VERSION 5.7 ;
BUSBITCHARS "[]" ;
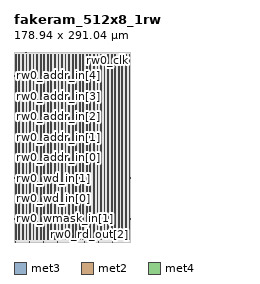
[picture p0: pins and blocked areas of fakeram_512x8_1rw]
MACRO fakeram_512x8_1rw
  FOREIGN fakeram_512x8_1rw 0 0 ;
  SYMMETRY X Y R90 ;
  SIZE 178.940 BY 291.040 ;
  CLASS BLOCK ;
  PIN rw0_wmask_in[0]
    DIRECTION INPUT ;
    USE SIGNAL ;
    SHAPE ABUTMENT ;
    PORT
      LAYER met3 ;
      RECT 0.000 3.930 0.900 4.230 ;
    END
  END rw0_wmask_in[0]
  PIN rw0_wmask_in[1]
    DIRECTION INPUT ;
    USE SIGNAL ;
    SHAPE ABUTMENT ;
    PORT
      LAYER met3 ;
      RECT 0.000 35.210 0.900 35.510 ;
    END
  END rw0_wmask_in[1]
  PIN rw0_wmask_in[2]
    DIRECTION INPUT ;
    USE SIGNAL ;
    SHAPE ABUTMENT ;
    PORT
      LAYER met3 ;
      RECT 178.040 3.930 178.940 4.230 ;
    END
  END rw0_wmask_in[2]
  PIN rw0_wmask_in[3]
    DIRECTION INPUT ;
    USE SIGNAL ;
    SHAPE ABUTMENT ;
    PORT
      LAYER met3 ;
      RECT 178.040 35.210 178.940 35.510 ;
    END
  END rw0_wmask_in[3]
  PIN rw0_wmask_in[4]
    DIRECTION INPUT ;
    USE SIGNAL ;
    SHAPE ABUTMENT ;
    PORT
      LAYER met2 ;
      RECT 2.690 290.620 2.830 291.040 ;
    END
  END rw0_wmask_in[4]
  PIN rw0_wmask_in[5]
    DIRECTION INPUT ;
    USE SIGNAL ;
    SHAPE ABUTMENT ;
    PORT
      LAYER met2 ;
      RECT 18.330 290.620 18.470 291.040 ;
    END
  END rw0_wmask_in[5]
  PIN rw0_wmask_in[6]
    DIRECTION INPUT ;
    USE SIGNAL ;
    SHAPE ABUTMENT ;
    PORT
      LAYER met2 ;
      RECT 33.970 290.620 34.110 291.040 ;
    END
  END rw0_wmask_in[6]
  PIN rw0_wmask_in[7]
    DIRECTION INPUT ;
    USE SIGNAL ;
    SHAPE ABUTMENT ;
    PORT
      LAYER met2 ;
      RECT 49.610 290.620 49.750 291.040 ;
    END
  END rw0_wmask_in[7]
  PIN rw0_wd_in[0]
    DIRECTION INPUT ;
    USE SIGNAL ;
    SHAPE ABUTMENT ;
    PORT
      LAYER met3 ;
      RECT 0.000 66.490 0.900 66.790 ;
    END
  END rw0_wd_in[0]
  PIN rw0_wd_in[1]
    DIRECTION INPUT ;
    USE SIGNAL ;
    SHAPE ABUTMENT ;
    PORT
      LAYER met3 ;
      RECT 0.000 97.770 0.900 98.070 ;
    END
  END rw0_wd_in[1]
  PIN rw0_wd_in[2]
    DIRECTION INPUT ;
    USE SIGNAL ;
    SHAPE ABUTMENT ;
    PORT
      LAYER met3 ;
      RECT 178.040 66.490 178.940 66.790 ;
    END
  END rw0_wd_in[2]
  PIN rw0_wd_in[3]
    DIRECTION INPUT ;
    USE SIGNAL ;
    SHAPE ABUTMENT ;
    PORT
      LAYER met3 ;
      RECT 178.040 97.770 178.940 98.070 ;
    END
  END rw0_wd_in[3]
  PIN rw0_wd_in[4]
    DIRECTION INPUT ;
    USE SIGNAL ;
    SHAPE ABUTMENT ;
    PORT
      LAYER met2 ;
      RECT 2.690 0.000 2.830 0.420 ;
    END
  END rw0_wd_in[4]
  PIN rw0_wd_in[5]
    DIRECTION INPUT ;
    USE SIGNAL ;
    SHAPE ABUTMENT ;
    PORT
      LAYER met2 ;
      RECT 23.850 0.000 23.990 0.420 ;
    END
  END rw0_wd_in[5]
  PIN rw0_wd_in[6]
    DIRECTION INPUT ;
    USE SIGNAL ;
    SHAPE ABUTMENT ;
    PORT
      LAYER met2 ;
      RECT 45.010 0.000 45.150 0.420 ;
    END
  END rw0_wd_in[6]
  PIN rw0_wd_in[7]
    DIRECTION INPUT ;
    USE SIGNAL ;
    SHAPE ABUTMENT ;
    PORT
      LAYER met2 ;
      RECT 66.170 0.000 66.310 0.420 ;
    END
  END rw0_wd_in[7]
  PIN rw0_rd_out[0]
    DIRECTION OUTPUT ;
    USE SIGNAL ;
    SHAPE ABUTMENT ;
    PORT
      LAYER met2 ;
      RECT 87.330 0.000 87.470 0.420 ;
    END
  END rw0_rd_out[0]
  PIN rw0_rd_out[1]
    DIRECTION OUTPUT ;
    USE SIGNAL ;
    SHAPE ABUTMENT ;
    PORT
      LAYER met2 ;
      RECT 108.490 0.000 108.630 0.420 ;
    END
  END rw0_rd_out[1]
  PIN rw0_rd_out[2]
    DIRECTION OUTPUT ;
    USE SIGNAL ;
    SHAPE ABUTMENT ;
    PORT
      LAYER met2 ;
      RECT 129.650 0.000 129.790 0.420 ;
    END
  END rw0_rd_out[2]
  PIN rw0_rd_out[3]
    DIRECTION OUTPUT ;
    USE SIGNAL ;
    SHAPE ABUTMENT ;
    PORT
      LAYER met2 ;
      RECT 150.810 0.000 150.950 0.420 ;
    END
  END rw0_rd_out[3]
  PIN rw0_rd_out[4]
    DIRECTION OUTPUT ;
    USE SIGNAL ;
    SHAPE ABUTMENT ;
    PORT
      LAYER met2 ;
      RECT 65.250 290.620 65.390 291.040 ;
    END
  END rw0_rd_out[4]
  PIN rw0_rd_out[5]
    DIRECTION OUTPUT ;
    USE SIGNAL ;
    SHAPE ABUTMENT ;
    PORT
      LAYER met2 ;
      RECT 80.890 290.620 81.030 291.040 ;
    END
  END rw0_rd_out[5]
  PIN rw0_rd_out[6]
    DIRECTION OUTPUT ;
    USE SIGNAL ;
    SHAPE ABUTMENT ;
    PORT
      LAYER met2 ;
      RECT 96.530 290.620 96.670 291.040 ;
    END
  END rw0_rd_out[6]
  PIN rw0_rd_out[7]
    DIRECTION OUTPUT ;
    USE SIGNAL ;
    SHAPE ABUTMENT ;
    PORT
      LAYER met2 ;
      RECT 112.170 290.620 112.310 291.040 ;
    END
  END rw0_rd_out[7]
  PIN rw0_addr_in[0]
    DIRECTION INPUT ;
    USE SIGNAL ;
    SHAPE ABUTMENT ;
    PORT
      LAYER met3 ;
      RECT 0.000 129.050 0.900 129.350 ;
    END
  END rw0_addr_in[0]
  PIN rw0_addr_in[1]
    DIRECTION INPUT ;
    USE SIGNAL ;
    SHAPE ABUTMENT ;
    PORT
      LAYER met3 ;
      RECT 0.000 160.330 0.900 160.630 ;
    END
  END rw0_addr_in[1]
  PIN rw0_addr_in[2]
    DIRECTION INPUT ;
    USE SIGNAL ;
    SHAPE ABUTMENT ;
    PORT
      LAYER met3 ;
      RECT 0.000 191.610 0.900 191.910 ;
    END
  END rw0_addr_in[2]
  PIN rw0_addr_in[3]
    DIRECTION INPUT ;
    USE SIGNAL ;
    SHAPE ABUTMENT ;
    PORT
      LAYER met3 ;
      RECT 0.000 222.890 0.900 223.190 ;
    END
  END rw0_addr_in[3]
  PIN rw0_addr_in[4]
    DIRECTION INPUT ;
    USE SIGNAL ;
    SHAPE ABUTMENT ;
    PORT
      LAYER met3 ;
      RECT 0.000 254.170 0.900 254.470 ;
    END
  END rw0_addr_in[4]
  PIN rw0_addr_in[5]
    DIRECTION INPUT ;
    USE SIGNAL ;
    SHAPE ABUTMENT ;
    PORT
      LAYER met3 ;
      RECT 178.040 129.050 178.940 129.350 ;
    END
  END rw0_addr_in[5]
  PIN rw0_addr_in[6]
    DIRECTION INPUT ;
    USE SIGNAL ;
    SHAPE ABUTMENT ;
    PORT
      LAYER met3 ;
      RECT 178.040 160.330 178.940 160.630 ;
    END
  END rw0_addr_in[6]
  PIN rw0_addr_in[7]
    DIRECTION INPUT ;
    USE SIGNAL ;
    SHAPE ABUTMENT ;
    PORT
      LAYER met3 ;
      RECT 178.040 191.610 178.940 191.910 ;
    END
  END rw0_addr_in[7]
  PIN rw0_addr_in[8]
    DIRECTION INPUT ;
    USE SIGNAL ;
    SHAPE ABUTMENT ;
    PORT
      LAYER met3 ;
      RECT 178.040 222.890 178.940 223.190 ;
    END
  END rw0_addr_in[8]
  PIN rw0_we_in
    DIRECTION INPUT ;
    USE SIGNAL ;
    SHAPE ABUTMENT ;
    PORT
      LAYER met2 ;
      RECT 127.810 290.620 127.950 291.040 ;
    END
  END rw0_we_in
  PIN rw0_ce_in
    DIRECTION INPUT ;
    USE SIGNAL ;
    SHAPE ABUTMENT ;
    PORT
      LAYER met2 ;
      RECT 143.450 290.620 143.590 291.040 ;
    END
  END rw0_ce_in
  PIN rw0_clk
    DIRECTION INPUT ;
    USE SIGNAL ;
    SHAPE ABUTMENT ;
    PORT
      LAYER met2 ;
      RECT 159.090 290.620 159.230 291.040 ;
    END
  END rw0_clk
  PIN VSS
    DIRECTION INOUT ;
    USE GROUND ;
    PORT
      LAYER met4 ;
      RECT 2.160 4.080 3.360 286.960 ;
      RECT 13.040 4.080 14.240 286.960 ;
      RECT 23.920 4.080 25.120 286.960 ;
      RECT 34.800 4.080 36.000 286.960 ;
      RECT 45.680 4.080 46.880 286.960 ;
      RECT 56.560 4.080 57.760 286.960 ;
      RECT 67.440 4.080 68.640 286.960 ;
      RECT 78.320 4.080 79.520 286.960 ;
      RECT 89.200 4.080 90.400 286.960 ;
      RECT 100.080 4.080 101.280 286.960 ;
      RECT 110.960 4.080 112.160 286.960 ;
      RECT 121.840 4.080 123.040 286.960 ;
      RECT 132.720 4.080 133.920 286.960 ;
      RECT 143.600 4.080 144.800 286.960 ;
      RECT 154.480 4.080 155.680 286.960 ;
      RECT 165.360 4.080 166.560 286.960 ;
      RECT 176.240 4.080 177.440 286.960 ;
    END
  END VSS
  PIN VDD
    DIRECTION INOUT ;
    USE POWER ;
    PORT
      LAYER met4 ;
      RECT 7.600 4.080 8.800 286.960 ;
      RECT 18.480 4.080 19.680 286.960 ;
      RECT 29.360 4.080 30.560 286.960 ;
      RECT 40.240 4.080 41.440 286.960 ;
      RECT 51.120 4.080 52.320 286.960 ;
      RECT 62.000 4.080 63.200 286.960 ;
      RECT 72.880 4.080 74.080 286.960 ;
      RECT 83.760 4.080 84.960 286.960 ;
      RECT 94.640 4.080 95.840 286.960 ;
      RECT 105.520 4.080 106.720 286.960 ;
      RECT 116.400 4.080 117.600 286.960 ;
      RECT 127.280 4.080 128.480 286.960 ;
      RECT 138.160 4.080 139.360 286.960 ;
      RECT 149.040 4.080 150.240 286.960 ;
      RECT 159.920 4.080 161.120 286.960 ;
      RECT 170.800 4.080 172.000 286.960 ;
    END
  END VDD
  OBS
    LAYER met1 ;
    RECT 0 0 178.940 291.040 ;
    LAYER met2 ;
    RECT 0 0 178.940 291.040 ;
    LAYER met3 ;
    RECT 0 0 178.940 291.040 ;
    LAYER met4 ;
    RECT 0 0 178.940 291.040 ;
  END
END fakeram_512x8_1rw

END LIBRARY
